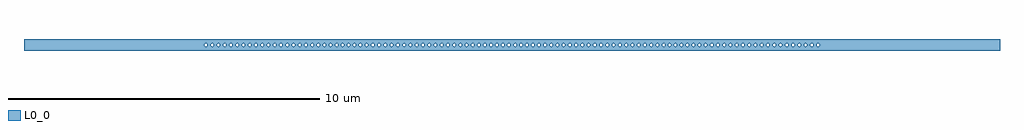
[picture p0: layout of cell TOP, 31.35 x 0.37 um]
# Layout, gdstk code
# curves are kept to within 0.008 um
import gdstk
lib = gdstk.Library(unit=1e-6, precision=1e-09)
def P(c, l, *ps):  # polygons
    for p in ps: c.add(gdstk.Polygon(p, *l))
L0_0 = (0, 0)

top = lib.new_cell('TOP')
P(top, L0_0, [(0,0),(0,0),(0,0),(0,0)],
  [(-8.211,0.049),(-8.196,0.042),(-8.184,0.031),(-8.176,0.016),(-8.175,0.011),(-8.175,0.183),(-15.675,0.183),(-15.675,0.05),(-8.228,0.05)],
  [(-8.175,-0.008),(-8.184,-0.031),(-8.211,-0.049),(-8.257,-0.037),(-8.273,-0.008),(-8.268,0.024),(-8.228,0.05),(-8.429,0.05),(-8.397,0.042),(-8.374,0),(-8.397,-0.042),(-8.429,-0.05),(-8.458,-0.037),(-8.474,-0.008),(-8.469,0.024),(-8.429,0.05),(-8.63,0.05),(-8.598,0.042),(-8.575,0),(-8.598,-0.042),(-8.63,-0.05),(-8.659,-0.037),(-8.675,-0.008),(-8.67,0.024),(-8.63,0.05),(-8.831,0.05),(-8.799,0.042),(-8.776,0),(-8.799,-0.042),(-8.831,-0.05),(-8.86,-0.037),(-8.876,-0.008),(-8.871,0.024),(-8.831,0.05),(-9.032,0.05),(-9,0.042),(-8.977,0),(-9,-0.042),(-9.032,-0.05),(-9.061,-0.037),(-9.077,-0.008),(-9.072,0.024),(-9.032,0.05),(-9.233,0.05),(-9.201,0.042),(-9.178,0),(-9.201,-0.042),(-9.233,-0.05),(-9.262,-0.037),(-9.278,-0.008),(-9.273,0.024),(-9.233,0.05),(-9.434,0.05),(-9.402,0.042),(-9.379,0),(-9.402,-0.042),(-9.434,-0.05),(-9.463,-0.037),(-9.479,-0.008),(-9.474,0.024),(-9.434,0.05),(-9.635,0.05),(-9.603,0.042),(-9.58,0),(-9.603,-0.042),(-9.635,-0.05),(-9.664,-0.037),(-9.68,-0.008),(-9.675,0.024),(-9.635,0.05),(-9.836,0.05),(-9.804,0.042),(-9.781,0),(-9.804,-0.042),(-9.836,-0.05),(-9.865,-0.037),(-9.881,-0.008),(-9.876,0.024),(-9.836,0.05),(-15.675,0.05),(-15.675,-0.183),(-8.175,-0.183)],
  [(-6.406,0.049),(-6.37,0.016),(-6.37,-0.016),(-6.39,-0.042),(-6.422,-0.05),(-6.452,-0.037),(-6.467,-0.008),(-6.452,0.037),(-6.422,0.05),(-6.622,0.05),(-6.59,0.042),(-6.567,0),(-6.59,-0.042),(-6.622,-0.05),(-6.651,-0.037),(-6.666,-0.008),(-6.661,0.024),(-6.622,0.05),(-6.822,0.05),(-6.79,0.042),(-6.767,0),(-6.79,-0.042),(-6.822,-0.05),(-6.851,-0.037),(-6.866,-0.008),(-6.862,0.024),(-6.822,0.05),(-7.022,0.05),(-6.99,0.042),(-6.968,0),(-6.99,-0.042),(-7.022,-0.05),(-7.052,-0.037),(-7.067,-0.008),(-7.052,0.037),(-7.022,0.05),(-7.223,0.05),(-7.179,0.031),(-7.169,0),(-7.179,-0.031),(-7.223,-0.05),(-7.253,-0.037),(-7.268,-0.008),(-7.253,0.037),(-7.223,0.05),(-7.424,0.05),(-7.38,0.031),(-7.37,0),(-7.38,-0.031),(-7.424,-0.05),(-7.454,-0.037),(-7.469,-0.008),(-7.454,0.037),(-7.424,0.05),(-7.625,0.05),(-7.593,0.042),(-7.57,0),(-7.593,-0.042),(-7.625,-0.05),(-7.654,-0.037),(-7.67,-0.008),(-7.665,0.024),(-7.625,0.05),(-7.826,0.05),(-7.794,0.042),(-7.771,0),(-7.794,-0.042),(-7.826,-0.05),(-7.855,-0.037),(-7.871,-0.008),(-7.866,0.024),(-7.826,0.05),(-8.027,0.05),(-7.995,0.042),(-7.972,0),(-7.995,-0.042),(-8.027,-0.05),(-8.056,-0.037),(-8.072,-0.008),(-8.067,0.024),(-8.027,0.05),(-8.175,0.05),(-8.175,-0.183),(-6.268,-0.183),(-6.268,0.183),(-8.175,0.183),(-8.175,0.05)],
  [(-6.253,0.037),(-6.239,0.046),(-6.224,0.05),(-6.268,0.05),(-6.268,0.008),(-6.264,0.024)],
  [(-6.268,0.183),(-6.268,0.05),(-4.675,0.05),(-4.643,0.042),(-4.621,0),(-4.643,-0.042),(-4.675,-0.05),(-4.705,-0.037),(-4.72,-0.008),(-4.705,0.037),(-4.675,0.05),(-4.876,0.05),(-4.844,0.042),(-4.822,0),(-4.844,-0.042),(-4.876,-0.05),(-4.906,-0.037),(-4.921,-0.008),(-4.906,0.037),(-4.876,0.05),(-5.065,0.05),(-5.033,0.042),(-5.011,0),(-5.033,-0.042),(-5.065,-0.05),(-5.095,-0.037),(-5.11,-0.008),(-5.095,0.037),(-5.065,0.05),(-5.255,0.05),(-5.223,0.042),(-5.2,0),(-5.223,-0.042),(-5.255,-0.05),(-5.284,-0.037),(-5.299,-0.008),(-5.295,0.024),(-5.255,0.05),(-5.445,0.05),(-5.401,0.031),(-5.391,0),(-5.401,-0.031),(-5.445,-0.05),(-5.475,-0.037),(-5.49,-0.008),(-5.475,0.037),(-5.445,0.05),(-5.637,0.05),(-5.593,0.031),(-5.583,0),(-5.593,-0.031),(-5.637,-0.05),(-5.667,-0.037),(-5.682,-0.008),(-5.667,0.037),(-5.637,0.05),(-5.831,0.05),(-5.787,0.031),(-5.777,0),(-5.787,-0.031),(-5.831,-0.05),(-5.861,-0.037),(-5.876,-0.008),(-5.861,0.037),(-5.831,0.05),(-6.027,0.05),(-5.995,0.042),(-5.972,0),(-5.995,-0.042),(-6.027,-0.05),(-6.056,-0.037),(-6.071,-0.008),(-6.066,0.024),(-6.027,0.05),(-6.224,0.05),(-6.18,0.031),(-6.172,-0.016),(-6.192,-0.042),(-6.224,-0.05),(-6.253,-0.037),(-6.268,-0.008),(-6.268,-0.183),(-4.504,-0.183),(-4.504,-0.037),(-4.519,-0.008),(-4.504,0.037),(-4.504,0.183)],
  [(-2.649,0.049),(-2.649,0.183),(-4.504,0.183),(-4.504,0.05),(-2.665,0.05)],
  [(-2.649,-0.049),(-2.695,-0.037),(-2.71,-0.008),(-2.695,0.037),(-2.665,0.05),(-2.866,0.05),(-2.834,0.042),(-2.812,0),(-2.834,-0.042),(-2.866,-0.05),(-2.896,-0.037),(-2.911,-0.008),(-2.896,0.037),(-2.866,0.05),(-3.067,0.05),(-3.035,0.042),(-3.013,0),(-3.035,-0.042),(-3.067,-0.05),(-3.097,-0.037),(-3.112,-0.008),(-3.097,0.037),(-3.067,0.05),(-3.268,0.05),(-3.236,0.042),(-3.214,0),(-3.236,-0.042),(-3.268,-0.05),(-3.298,-0.037),(-3.313,-0.008),(-3.298,0.037),(-3.268,0.05),(-3.469,0.05),(-3.437,0.042),(-3.415,0),(-3.437,-0.042),(-3.469,-0.05),(-3.499,-0.037),(-3.514,-0.008),(-3.499,0.037),(-3.469,0.05),(-3.67,0.05),(-3.638,0.042),(-3.616,0),(-3.638,-0.042),(-3.67,-0.05),(-3.7,-0.037),(-3.715,-0.008),(-3.7,0.037),(-3.67,0.05),(-3.871,0.05),(-3.839,0.042),(-3.817,0),(-3.839,-0.042),(-3.871,-0.05),(-3.901,-0.037),(-3.916,-0.008),(-3.901,0.037),(-3.871,0.05),(-4.072,0.05),(-4.04,0.042),(-4.018,0),(-4.04,-0.042),(-4.072,-0.05),(-4.102,-0.037),(-4.117,-0.008),(-4.102,0.037),(-4.072,0.05),(-4.273,0.05),(-4.241,0.042),(-4.219,0),(-4.241,-0.042),(-4.273,-0.05),(-4.303,-0.037),(-4.318,-0.008),(-4.303,0.037),(-4.273,0.05),(-4.474,0.05),(-4.431,0.031),(-4.422,-0.016),(-4.458,-0.049),(-4.504,-0.037),(-4.504,-0.183),(-2.649,-0.183)],
  [(-4.49,0.046),(-4.474,0.05),(-4.504,0.05),(-4.504,0.037)],
  [(-0.855,0.049),(-0.84,0.042),(-0.84,0.183),(-2.649,0.183),(-2.649,0.05),(-0.871,0.05)],
  [(-0.84,-0.042),(-0.887,-0.046),(-0.911,-0.024),(-0.911,0.024),(-0.871,0.05),(-1.067,0.05),(-1.023,0.031),(-1.013,0),(-1.023,-0.031),(-1.067,-0.05),(-1.097,-0.037),(-1.112,-0.008),(-1.097,0.037),(-1.067,0.05),(-1.264,0.05),(-1.232,0.042),(-1.21,0),(-1.232,-0.042),(-1.264,-0.05),(-1.294,-0.037),(-1.309,-0.008),(-1.294,0.037),(-1.264,0.05),(-1.463,0.05),(-1.431,0.042),(-1.408,0),(-1.431,-0.042),(-1.463,-0.05),(-1.492,-0.037),(-1.507,-0.008),(-1.503,0.024),(-1.463,0.05),(-1.662,0.05),(-1.63,0.042),(-1.608,0),(-1.63,-0.042),(-1.662,-0.05),(-1.692,-0.037),(-1.707,-0.008),(-1.692,0.037),(-1.662,0.05),(-1.862,0.05),(-1.83,0.042),(-1.808,0),(-1.83,-0.042),(-1.862,-0.05),(-1.892,-0.037),(-1.907,-0.008),(-1.892,0.037),(-1.862,0.05),(-2.063,0.05),(-2.031,0.042),(-2.008,0),(-2.031,-0.042),(-2.063,-0.05),(-2.092,-0.037),(-2.108,-0.008),(-2.103,0.024),(-2.063,0.05),(-2.264,0.05),(-2.232,0.042),(-2.209,0),(-2.232,-0.042),(-2.264,-0.05),(-2.293,-0.037),(-2.308,-0.008),(-2.303,0.024),(-2.264,0.05),(-2.464,0.05),(-2.432,0.042),(-2.41,0),(-2.432,-0.042),(-2.464,-0.05),(-2.494,-0.037),(-2.509,-0.008),(-2.494,0.037),(-2.464,0.05),(-2.649,0.05),(-2.622,0.031),(-2.611,0),(-2.622,-0.031),(-2.649,-0.049),(-2.649,-0.183),(-0.84,-0.183)],
  [(0.879,0.049),(0.895,0.042),(0.895,0.183),(-0.84,0.183),(-0.84,0.05),(0.863,0.05)],
  [(0.895,-0.042),(0.863,-0.05),(0.823,-0.024),(0.823,0.024),(0.863,0.05),(0.669,0.05),(0.713,0.031),(0.723,0),(0.713,-0.031),(0.669,-0.05),(0.639,-0.037),(0.624,-0.008),(0.639,0.037),(0.669,0.05),(0.477,0.05),(0.521,0.031),(0.531,0),(0.521,-0.031),(0.477,-0.05),(0.447,-0.037),(0.432,-0.008),(0.447,0.037),(0.477,0.05),(0.287,0.05),(0.33,0.031),(0.341,0),(0.33,-0.031),(0.287,-0.05),(0.257,-0.037),(0.242,-0.008),(0.257,0.037),(0.287,0.05),(0.097,0.05),(0.129,0.042),(0.152,0),(0.129,-0.042),(0.097,-0.05),(0.067,-0.037),(0.052,-0.008),(0.067,0.037),(0.097,0.05),(-0.106,0.05),(-0.074,0.042),(-0.051,0),(-0.074,-0.042),(-0.106,-0.05),(-0.136,-0.037),(-0.151,-0.008),(-0.136,0.037),(-0.106,0.05),(-0.295,0.05),(-0.263,0.042),(-0.241,0),(-0.263,-0.042),(-0.295,-0.05),(-0.325,-0.037),(-0.34,-0.008),(-0.325,0.037),(-0.295,0.05),(-0.486,0.05),(-0.454,0.042),(-0.431,0),(-0.454,-0.042),(-0.486,-0.05),(-0.515,-0.037),(-0.53,-0.008),(-0.525,0.024),(-0.486,0.05),(-0.678,0.05),(-0.646,0.042),(-0.623,0),(-0.646,-0.042),(-0.678,-0.05),(-0.707,-0.037),(-0.722,-0.008),(-0.717,0.024),(-0.678,0.05),(-0.84,0.05),(-0.817,0),(-0.84,-0.042),(-0.84,-0.183),(0.895,-0.183)],
  [(2.673,0.049),(2.689,0.042),(2.7,0.031),(2.7,0.183),(0.895,0.183),(0.895,0.05),(2.657,0.05)],
  [(2.7,-0.031),(2.657,-0.05),(2.617,-0.024),(2.617,0.024),(2.657,0.05),(2.456,0.05),(2.488,0.042),(2.51,0),(2.488,-0.042),(2.456,-0.05),(2.426,-0.037),(2.411,-0.008),(2.426,0.037),(2.456,0.05),(2.255,0.05),(2.287,0.042),(2.309,0),(2.287,-0.042),(2.255,-0.05),(2.225,-0.037),(2.21,-0.008),(2.225,0.037),(2.255,0.05),(2.054,0.05),(2.098,0.031),(2.108,0),(2.098,-0.031),(2.054,-0.05),(2.024,-0.037),(2.009,-0.008),(2.024,0.037),(2.054,0.05),(1.854,0.05),(1.897,0.031),(1.908,0),(1.897,-0.031),(1.854,-0.05),(1.824,-0.037),(1.809,-0.008),(1.824,0.037),(1.854,0.05),(1.653,0.05),(1.685,0.042),(1.708,0),(1.685,-0.042),(1.653,-0.05),(1.624,-0.037),(1.609,-0.008),(1.614,0.024),(1.653,0.05),(1.454,0.05),(1.498,0.031),(1.508,0),(1.498,-0.031),(1.454,-0.05),(1.424,-0.037),(1.409,-0.008),(1.424,0.037),(1.454,0.05),(1.256,0.05),(1.299,0.031),(1.31,0),(1.299,-0.031),(1.256,-0.05),(1.226,-0.037),(1.211,-0.008),(1.226,0.037),(1.256,0.05),(1.058,0.05),(1.09,0.042),(1.113,0),(1.09,-0.042),(1.058,-0.05),(1.029,-0.037),(1.014,-0.008),(1.019,0.024),(1.058,0.05),(0.895,0.05),(0.917,0),(0.895,-0.042),(0.895,-0.183),(2.7,-0.183)],
  [(4.281,0.049),(4.308,0.031),(4.319,0),(4.297,-0.042),(4.265,-0.05),(4.235,-0.037),(4.22,-0.008),(4.235,0.037),(4.265,0.05),(4.064,0.05),(4.096,0.042),(4.118,0),(4.096,-0.042),(4.064,-0.05),(4.034,-0.037),(4.019,-0.008),(4.034,0.037),(4.064,0.05),(3.863,0.05),(3.895,0.042),(3.917,0),(3.895,-0.042),(3.863,-0.05),(3.833,-0.037),(3.818,-0.008),(3.833,0.037),(3.863,0.05),(3.662,0.05),(3.694,0.042),(3.716,0),(3.694,-0.042),(3.662,-0.05),(3.632,-0.037),(3.617,-0.008),(3.632,0.037),(3.662,0.05),(3.461,0.05),(3.493,0.042),(3.515,0),(3.493,-0.042),(3.461,-0.05),(3.431,-0.037),(3.416,-0.008),(3.431,0.037),(3.461,0.05),(3.26,0.05),(3.292,0.042),(3.314,0),(3.292,-0.042),(3.26,-0.05),(3.23,-0.037),(3.215,-0.008),(3.23,0.037),(3.26,0.05),(3.059,0.05),(3.091,0.042),(3.113,0),(3.091,-0.042),(3.059,-0.05),(3.029,-0.037),(3.014,-0.008),(3.029,0.037),(3.059,0.05),(2.858,0.05),(2.89,0.042),(2.912,0),(2.89,-0.042),(2.858,-0.05),(2.828,-0.037),(2.813,-0.008),(2.828,0.037),(2.858,0.05),(2.7,0.05),(2.711,0),(2.7,-0.031),(2.7,-0.183),(4.466,-0.183),(4.466,-0.05),(4.436,-0.037),(4.421,-0.008),(4.436,0.037),(4.466,0.05),(4.466,0.183),(2.7,0.183),(2.7,0.05)],
  [(6.034,0.049),(6.07,0.016),(6.07,-0.016),(6.05,-0.042),(6.018,-0.05),(5.988,-0.037),(5.973,-0.008),(5.988,0.037),(6.018,0.05),(5.822,0.05),(5.854,0.042),(5.877,0),(5.854,-0.042),(5.822,-0.05),(5.793,-0.037),(5.777,-0.008),(5.782,0.024),(5.822,0.05),(5.628,0.05),(5.66,0.042),(5.683,0),(5.66,-0.042),(5.628,-0.05),(5.599,-0.037),(5.584,-0.008),(5.589,0.024),(5.628,0.05),(5.436,0.05),(5.468,0.042),(5.491,0),(5.468,-0.042),(5.436,-0.05),(5.407,-0.037),(5.392,-0.008),(5.397,0.024),(5.436,0.05),(5.246,0.05),(5.29,0.031),(5.3,0),(5.29,-0.031),(5.246,-0.05),(5.216,-0.037),(5.201,-0.008),(5.216,0.037),(5.246,0.05),(5.057,0.05),(5.089,0.042),(5.111,0),(5.089,-0.042),(5.057,-0.05),(5.027,-0.037),(5.012,-0.008),(5.027,0.037),(5.057,0.05),(4.868,0.05),(4.9,0.042),(4.922,0),(4.9,-0.042),(4.868,-0.05),(4.838,-0.037),(4.823,-0.008),(4.838,0.037),(4.868,0.05),(4.667,0.05),(4.699,0.042),(4.721,0),(4.699,-0.042),(4.667,-0.05),(4.637,-0.037),(4.622,-0.008),(4.637,0.037),(4.667,0.05),(4.466,0.05),(4.498,0.042),(4.52,0),(4.498,-0.042),(4.466,-0.05),(4.466,-0.183),(6.215,-0.183),(6.215,-0.05),(6.185,-0.037),(6.17,-0.008),(6.185,0.037),(6.215,0.05),(6.215,0.183),(4.466,0.183),(4.466,0.05)],
  [(8.034,0.049),(8.034,0.183),(6.215,0.183),(6.215,0.05),(8.018,0.05)],
  [(8.034,-0.049),(7.988,-0.037),(7.973,-0.008),(7.988,0.037),(8.018,0.05),(7.817,0.05),(7.861,0.031),(7.871,0),(7.861,-0.031),(7.817,-0.05),(7.787,-0.037),(7.772,-0.008),(7.787,0.037),(7.817,0.05),(7.616,0.05),(7.66,0.031),(7.67,0),(7.66,-0.031),(7.616,-0.05),(7.586,-0.037),(7.571,-0.008),(7.586,0.037),(7.616,0.05),(7.415,0.05),(7.447,0.042),(7.47,0),(7.447,-0.042),(7.415,-0.05),(7.385,-0.037),(7.37,-0.008),(7.385,0.037),(7.415,0.05),(7.214,0.05),(7.246,0.042),(7.269,0),(7.246,-0.042),(7.214,-0.05),(7.185,-0.037),(7.17,-0.008),(7.174,0.024),(7.214,0.05),(7.014,0.05),(7.057,0.031),(7.068,0),(7.057,-0.031),(7.014,-0.05),(6.984,-0.037),(6.969,-0.008),(6.984,0.037),(7.014,0.05),(6.813,0.05),(6.857,0.031),(6.867,0),(6.857,-0.031),(6.813,-0.05),(6.783,-0.037),(6.768,-0.008),(6.783,0.037),(6.813,0.05),(6.613,0.05),(6.657,0.031),(6.667,0),(6.657,-0.031),(6.613,-0.05),(6.583,-0.037),(6.568,-0.008),(6.583,0.037),(6.613,0.05),(6.413,0.05),(6.445,0.042),(6.468,0),(6.445,-0.042),(6.413,-0.05),(6.384,-0.037),(6.369,-0.008),(6.374,0.024),(6.413,0.05),(6.215,0.05),(6.259,0.031),(6.269,0),(6.259,-0.031),(6.215,-0.05),(6.215,-0.183),(8.034,-0.183)],
  [(8.05,0.042),(8.07,0.016),(8.071,-0.008),(8.174,-0.008),(8.189,0.037),(8.219,0.05),(8.263,0.031),(8.272,-0.008),(8.375,-0.008),(8.39,0.037),(8.42,0.05),(8.464,0.031),(8.473,-0.008),(8.576,-0.008),(8.591,0.037),(8.621,0.05),(8.665,0.031),(8.674,-0.008),(8.777,-0.008),(8.792,0.037),(8.822,0.05),(8.866,0.031),(8.876,0),(8.866,-0.031),(8.822,-0.05),(8.792,-0.037),(8.777,-0.008),(8.674,-0.008),(8.653,-0.042),(8.621,-0.05),(8.591,-0.037),(8.576,-0.008),(8.473,-0.008),(8.452,-0.042),(8.42,-0.05),(8.39,-0.037),(8.375,-0.008),(8.272,-0.008),(8.251,-0.042),(8.219,-0.05),(8.189,-0.037),(8.174,-0.008),(8.071,-0.008),(8.062,-0.031),(8.034,-0.049),(8.034,-0.183),(8.993,-0.183),(8.993,-0.037),(8.978,-0.008),(8.993,0.037),(8.993,0.183),(8.034,0.183),(8.034,0.049)],
  [(9.023,0.05),(9.067,0.031),(9.076,-0.008),(9.179,-0.008),(9.194,0.037),(9.224,0.05),(9.268,0.031),(9.277,-0.008),(9.38,-0.008),(9.395,0.037),(9.425,0.05),(9.469,0.031),(9.478,-0.008),(9.581,-0.008),(9.596,0.037),(9.626,0.05),(9.67,0.031),(9.679,-0.008),(9.782,-0.008),(9.797,0.037),(9.843,0.049),(9.871,0.031),(9.879,-0.016),(9.859,-0.042),(9.827,-0.05),(9.797,-0.037),(9.782,-0.008),(9.679,-0.008),(9.658,-0.042),(9.626,-0.05),(9.596,-0.037),(9.581,-0.008),(9.478,-0.008),(9.457,-0.042),(9.425,-0.05),(9.395,-0.037),(9.38,-0.008),(9.277,-0.008),(9.256,-0.042),(9.224,-0.05),(9.194,-0.037),(9.179,-0.008),(9.076,-0.008),(9.067,-0.031),(9.039,-0.049),(8.993,-0.037),(8.993,-0.183),(15.675,-0.183),(15.675,0.183),(8.993,0.183),(8.993,0.037)])

lib.write_gds('TOP.gds')
